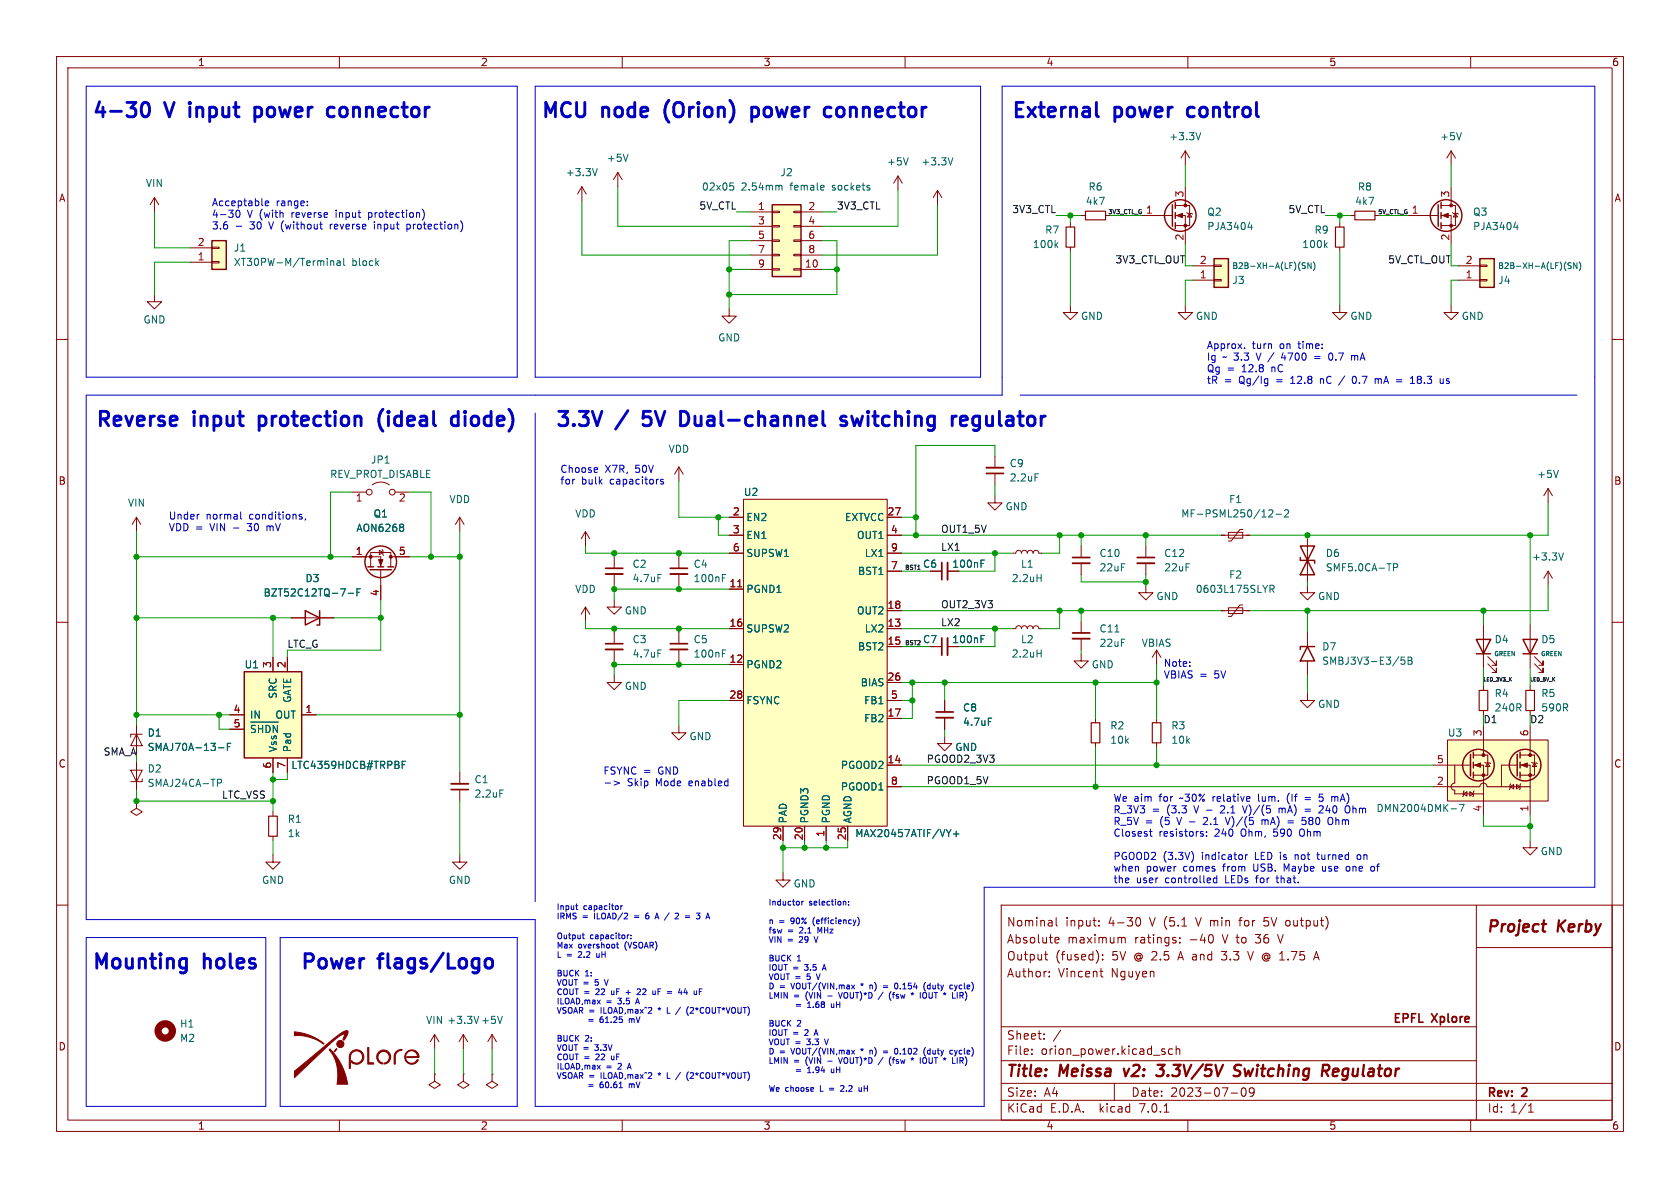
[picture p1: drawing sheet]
<svg xmlns="http://www.w3.org/2000/svg" width="297mm" height="210mm" viewBox="0 0 297 210" stroke-linecap="round" stroke-linejoin="round" font-family="sans-serif">
<defs><g id="words">
<g font-size="3.5" fill="#0000c2">
<text x="16.5" y="21">4-30</text>
<text x="29.6" y="21">V</text>
<text x="34.5" y="21">input</text>
<text x="46.7" y="21">power</text>
<text x="60.4" y="21">connector</text>
<text x="95.9" y="21">MCU</text>
<text x="106.7" y="21">node</text>
<text x="118.5" y="21">(Orion)</text>
<text x="134.6" y="21">power</text>
<text x="148.3" y="21">connector</text>
<text x="179.1" y="21">External</text>
<text x="197.2" y="21">power</text>
<text x="211" y="21">control</text>
<text x="17.1" y="75.6">Reverse</text>
<text x="34.5" y="75.6">input</text>
<text x="46.7" y="75.6">protection</text>
<text x="68.7" y="75.6">(ideal</text>
<text x="82.4" y="75.6">diode)</text>
<text x="98.4" y="75.6">3.3V</text>
<text x="109.3" y="75.6">/</text>
<text x="114.7" y="75.6">5V</text>
<text x="122" y="75.6">Dual-channel</text>
<text x="151.2" y="75.6">switching</text>
<text x="171.5" y="75.6">regulator</text>
<text x="16.5" y="171.5">Mounting</text>
<text x="36.3" y="171.5">holes</text>
<text x="53.3" y="171.5">Power</text>
<text x="67.3" y="171.5">flags/Logo</text>
</g>
<g font-size="2.8" fill="#840000">
<text x="262.7" y="165.3">Project</text>
<text x="275.2" y="165.3">Kerby</text>
<text x="178" y="190.8">Title:</text>
<text x="187.4" y="190.8">Meissa</text>
<text x="199.4" y="190.8">v2:</text>
<text x="205.9" y="190.8">3.3V/5V</text>
<text x="220.1" y="190.8">Switching</text>
<text x="236.2" y="190.8">Regulator</text>
</g>
<g font-size="2.1" fill="#840000">
<text x="178" y="166.9">Absolute</text>
<text x="178" y="163.9">Nominal</text>
<text x="188.4" y="163.9">input:</text>
<text x="188.7" y="166.9">maximum</text>
<text x="195.9" y="163.9">4-30</text>
<text x="200.6" y="166.9">ratings:</text>
<text x="203.3" y="163.9">V (5.1</text>
<text x="210.3" y="166.9">-40</text>
<text x="211.6" y="163.9">V min</text>
<text x="216.3" y="166.9">V to</text>
<text x="219.4" y="163.9">for</text>
<text x="222.2" y="166.9">36</text>
<text x="223.8" y="163.9">5V output)</text>
<text x="226.3" y="166.9">V</text>
<text x="178" y="172.9">Author:</text>
<text x="178" y="169.9">Output</text>
<text x="186.6" y="169.9">(fused):</text>
<text x="187.1" y="172.9">Vincent</text>
<text x="196.4" y="172.9">Nguyen</text>
<text x="196.6" y="169.9">5V @ 2.5</text>
<text x="208.5" y="169.9">A and</text>
<text x="216.3" y="169.9">3.3</text>
<text x="221.1" y="169.9">V @ 1.75</text>
<text x="233" y="169.9">A</text>
<text x="178" y="183.9">Sheet:</text>
<text x="186.2" y="183.9">/</text>
<text x="245.9" y="181.1">EPFL</text>
<text x="252.9" y="181.1">Xplore</text>
<text x="178" y="186.6">File:</text>
<text x="184" y="186.6">orion_power.kicad_sch</text>
<text x="178" y="196.8">KiCad</text>
<text x="178" y="194">Size:</text>
<text x="184.6" y="194">A4</text>
<text x="185.7" y="196.8">E.D.A.</text>
<text x="194.4" y="196.8">kicad</text>
<text x="200" y="194">Date:</text>
<text x="201.5" y="196.8">7.0.1</text>
<text x="206.9" y="194">2023-07-09</text>
<text x="263" y="194.2">Rev:</text>
<text x="263" y="196.8">Id:</text>
<text x="267" y="196.8">1/1</text>
<text x="269.2" y="194.2">2</text>
</g>
<g font-size="1.8" fill="#840000">
<text x="35" y="11.8">1</text>
<text x="85" y="11.8">2</text>
<text x="135" y="11.8">3</text>
<text x="185" y="11.8">4</text>
<text x="235" y="11.8">5</text>
<text x="285" y="11.8">6</text>
<text x="10.4" y="35.8">A</text>
<text x="285.4" y="35.8">A</text>
<text x="10.3" y="85.8">B</text>
<text x="285.3" y="85.8">B</text>
<text x="10.3" y="135.8">C</text>
<text x="285.3" y="135.8">C</text>
<text x="10.3" y="185.8">D</text>
<text x="285.3" y="185.8">D</text>
<text x="35" y="199.8">1</text>
<text x="85" y="199.8">2</text>
<text x="135" y="199.8">3</text>
<text x="185" y="199.8">4</text>
<text x="235" y="199.8">5</text>
<text x="285" y="199.8">6</text>
</g>
<g font-size="1.8" fill="#006464">
<text x="107.2" y="28.8">+5V</text>
<text x="156.8" y="29.4">+5V</text>
<text x="162.8" y="29.4">+3.3V</text>
<text x="206.6" y="25">+3.3V</text>
<text x="254.5" y="25">+5V</text>
<text x="25.7" y="33.2">VIN</text>
<text x="100" y="31.3">+3.3V</text>
<text x="124" y="33.8">02x05</text>
<text x="131" y="33.8">2.54mm</text>
<text x="137.9" y="31.3">J2</text>
<text x="139.7" y="33.8">female</text>
<text x="147.2" y="33.8">sockets</text>
<text x="192.4" y="33.8">R6</text>
<text x="240" y="33.8">R8</text>
<text x="184.7" y="41.5">R7</text>
<text x="191.9" y="36.4">4k7</text>
<text x="213.4" y="38.3">Q2</text>
<text x="213.4" y="40.8">PJA3404</text>
<text x="232.3" y="41.5">R9</text>
<text x="239.5" y="36.4">4k7</text>
<text x="260.4" y="38.3">Q3</text>
<text x="260.4" y="40.8">PJA3404</text>
<text x="41.3" y="44.6">J1</text>
<text x="41.3" y="47.2">XT30PW-M/Terminal</text>
<text x="62.2" y="47.2">block</text>
<text x="182.5" y="44">100k</text>
<text x="230.2" y="44">100k</text>
<text x="217.8" y="50.4">J3</text>
<text x="264.8" y="50.4">J4</text>
<text x="25.3" y="57.3">GND</text>
<text x="191" y="56.7">GND</text>
<text x="211.4" y="56.7">GND</text>
<text x="238.7" y="56.7">GND</text>
<text x="258.4" y="56.7">GND</text>
<text x="126.9" y="60.5">GND</text>
<text x="65.5" y="82.1">JP1</text>
<text x="118.1" y="80.2">VDD</text>
<text x="178.4" y="82.7">C9</text>
<text x="22.6" y="89.7">VIN</text>
<text x="58.3" y="84.6">REV_PROT_DISABLE</text>
<text x="79.4" y="89.1">VDD</text>
<text x="131.5" y="87.8">U2</text>
<text x="178.4" y="85.3">2.2uF</text>
<text x="217.2" y="89.1">F1</text>
<text x="271.7" y="84.6">+5V</text>
<text x="63" y="94.2">AON6268</text>
<text x="66" y="91.6">Q1</text>
<text x="101.6" y="91.6">VDD</text>
<text x="132" y="92.3">EN2</text>
<text x="132" y="95.4">EN1</text>
<text x="149.3" y="92.3">EXTVCC</text>
<text x="151.4" y="95.4">OUT1</text>
<text x="177.7" y="90.4">GND</text>
<text x="208.8" y="91.6">MF-PSML250/12-2</text>
<text x="111.8" y="100.5">C2</text>
<text x="122.6" y="100.5">C4</text>
<text x="132" y="98.6">SUPSW1</text>
<text x="151.6" y="101.8">BST1</text>
<text x="152.8" y="98.6">LX1</text>
<text x="163.1" y="100.5">C6</text>
<text x="168.3" y="100.5">100nF</text>
<text x="180.4" y="100.5">L1</text>
<text x="194.3" y="98.6">C10</text>
<text x="194.3" y="101.2">22uF</text>
<text x="205.7" y="98.6">C12</text>
<text x="205.7" y="101.2">22uF</text>
<text x="234.3" y="98.6">D6</text>
<text x="234.3" y="101.2">SMF5.0CA-TP</text>
<text x="270.8" y="99.3">+3.3V</text>
<text x="46.5" y="105.6">BZT52C12TQ-7-F</text>
<text x="53.9" y="103.1">D3</text>
<text x="101.6" y="105">VDD</text>
<text x="111.8" y="103.1">4.7uF</text>
<text x="122.6" y="103.1">100nF</text>
<text x="132" y="105">PGND1</text>
<text x="178.8" y="103.1">2.2uH</text>
<text x="204.4" y="106.2">GND</text>
<text x="211.3" y="105">0603L175SLYR</text>
<text x="217.2" y="102.4">F2</text>
<text x="233" y="106.2">GND</text>
<text x="110.4" y="108.8">GND</text>
<text x="111.8" y="113.9">C3</text>
<text x="122.6" y="113.9">C5</text>
<text x="132" y="112">SUPSW2</text>
<text x="151.4" y="108.8">OUT2</text>
<text x="152.8" y="112">LX2</text>
<text x="163.1" y="113.9">C7</text>
<text x="168.3" y="113.9">100nF</text>
<text x="180.4" y="113.9">L2</text>
<text x="194.3" y="112">C11</text>
<text x="264.2" y="113.9">D4</text>
<text x="272.4" y="113.9">D5</text>
<text x="43.2" y="118.3">U1</text>
<text x="111.8" y="116.4">4.7uF</text>
<text x="122.6" y="116.4">100nF</text>
<text x="132" y="118.3">PGND2</text>
<text x="151.6" y="115.1">BST2</text>
<text x="178.8" y="116.4">2.2uH</text>
<text x="192.9" y="118.3">GND</text>
<text x="194.3" y="114.5">22uF</text>
<text x="201.8" y="114.5">VBIAS</text>
<text x="233.7" y="115.1">D7</text>
<text x="233.7" y="117.7">SMBJ3V3-E3/5B</text>
<text x="49.1" y="123.6" transform="rotate(-90 49.1 123.6)">SRC</text>
<text x="51.6" y="124.4" transform="rotate(-90 51.6 124.4)">GATE</text>
<text x="110.4" y="122.1">GND</text>
<text x="132" y="124.7">FSYNC</text>
<text x="152" y="121.5">BIAS</text>
<text x="152.6" y="124.7">FB1</text>
<text x="170.2" y="125.9">C8</text>
<text x="233" y="125.3">GND</text>
<text x="264.2" y="123.4">R4</text>
<text x="264.2" y="125.9">240R</text>
<text x="272.4" y="123.4">R5</text>
<text x="272.4" y="125.9">590R</text>
<text x="26" y="130.4">D1</text>
<text x="44.2" y="127.2">IN</text>
<text x="44.2" y="130.3">~{SHDN}</text>
<text x="48.6" y="127.2">OUT</text>
<text x="121.8" y="131">GND</text>
<text x="152.6" y="127.8">FB2</text>
<text x="170.2" y="128.5">4.7uF</text>
<text x="196.2" y="129.1">R2</text>
<text x="196.2" y="131.6">10k</text>
<text x="207" y="129.1">R3</text>
<text x="207" y="131.6">10k</text>
<text x="255.9" y="130.4">U3</text>
<text x="26" y="132.9">SMAJ70A-13-F</text>
<text x="26" y="136.7">D2</text>
<text x="49.1" y="133" transform="rotate(-90 49.1 133)">Vss</text>
<text x="51.4" y="136.1">LTC4359HDCB#TRPBF</text>
<text x="51.6" y="133" transform="rotate(-90 51.6 133)">Pad</text>
<text x="148.5" y="136.1">PGOOD2</text>
<text x="168.8" y="132.9">GND</text>
<text x="26" y="139.3">SMAJ24CA-TP</text>
<text x="83.8" y="138.6">C1</text>
<text x="83.8" y="141.2">2.2uF</text>
<text x="148.5" y="139.9">PGOOD1</text>
<text x="50.8" y="145.6">R1</text>
<text x="50.8" y="148.1">1k</text>
<text x="139.3" y="145.5" transform="rotate(-90 139.3 145.5)">PAD</text>
<text x="143.1" y="145.5" transform="rotate(-90 143.1 145.5)">PGND3</text>
<text x="146.9" y="145.5" transform="rotate(-90 146.9 145.5)">PGND</text>
<text x="150.7" y="145.5" transform="rotate(-90 150.7 145.5)">AGND</text>
<text x="151.1" y="148.1">MAX20457ATIF/VY+</text>
<text x="272.3" y="151.3">GND</text>
<text x="46.3" y="156.4">GND</text>
<text x="79.3" y="156.4">GND</text>
<text x="140.2" y="157">GND</text>
<text x="31.8" y="181.8">H1</text>
<text x="31.8" y="184.3">M2</text>
<text x="75.3" y="181.2">VIN +3.3V</text>
<text x="85" y="181.2">+5V</text>
</g>
<g font-size="1.8" fill="#a90000">
<text x="209.3" y="35" transform="rotate(-90 209.3 35)">3</text>
<text x="256.3" y="35" transform="rotate(-90 256.3 35)">3</text>
<text x="134" y="37.2">1</text>
<text x="134" y="39.8">3</text>
<text x="142.8" y="37.2">2</text>
<text x="142.8" y="39.8">4</text>
<text x="202.5" y="37.8">1</text>
<text x="249.5" y="37.8">1</text>
<text x="34.9" y="46.1">1</text>
<text x="34.9" y="43.6">2</text>
<text x="134" y="42.3">5</text>
<text x="134" y="44.8">7</text>
<text x="134" y="47.4">9</text>
<text x="142.2" y="47.4">10</text>
<text x="142.8" y="42.3">6</text>
<text x="142.8" y="44.8">8</text>
<text x="209.3" y="42.6" transform="rotate(-90 209.3 42.6)">2</text>
<text x="212.1" y="46.7">2</text>
<text x="256.3" y="42.6" transform="rotate(-90 256.3 42.6)">2</text>
<text x="259" y="46.7">2</text>
<text x="212.1" y="49.3">1</text>
<text x="259" y="49.3">1</text>
<text x="62.8" y="88.9">1</text>
<text x="70.5" y="88.9">2</text>
<text x="129.5" y="91.2">2</text>
<text x="129.5" y="94.4">3</text>
<text x="156.8" y="91.2">27</text>
<text x="157.4" y="94.4">4</text>
<text x="62.8" y="98.2">1</text>
<text x="70.5" y="98.2">5</text>
<text x="129.5" y="97.5">6</text>
<text x="157.4" y="100.7">7</text>
<text x="157.4" y="97.5">9</text>
<text x="67.1" y="105.4" transform="rotate(-90 67.1 105.4)">4</text>
<text x="128.9" y="103.9">11</text>
<text x="156.8" y="107.7">18</text>
<text x="128.9" y="110.9">16</text>
<text x="156.8" y="110.9">13</text>
<text x="48" y="118.1" transform="rotate(-90 48 118.1)">3</text>
<text x="50.5" y="118.1" transform="rotate(-90 50.5 118.1)">2</text>
<text x="128.9" y="117.2">12</text>
<text x="156.8" y="114">15</text>
<text x="128.9" y="123.6">28</text>
<text x="156.8" y="120.4">26</text>
<text x="157.4" y="123.6">5</text>
<text x="41.2" y="126.1">4</text>
<text x="41.2" y="128.7">5</text>
<text x="53.9" y="126.1">1</text>
<text x="156.8" y="126.7">17</text>
<text x="262" y="130.2" transform="rotate(-90 262 130.2)">3</text>
<text x="270.3" y="130.2" transform="rotate(-90 270.3 130.2)">6</text>
<text x="48" y="135.9" transform="rotate(-90 48 135.9)">6</text>
<text x="50.5" y="135.9" transform="rotate(-90 50.5 135.9)">7</text>
<text x="156.8" y="135">14</text>
<text x="254" y="135">5</text>
<text x="157.4" y="138.8">8</text>
<text x="254" y="138.8">2</text>
<text x="262" y="143.5" transform="rotate(-90 262 143.5)">4</text>
<text x="270.3" y="143.5" transform="rotate(-90 270.3 143.5)">1</text>
<text x="138.2" y="148.6" transform="rotate(-90 138.2 148.6)">29</text>
<text x="142" y="148.6" transform="rotate(-90 142 148.6)">20</text>
<text x="145.8" y="148" transform="rotate(-90 145.8 148)">1</text>
<text x="149.6" y="148.6" transform="rotate(-90 149.6 148.6)">25</text>
</g>
<g font-size="1.8" fill="#0000c2">
<text x="37.5" y="36.5">Acceptable</text>
<text x="37.5" y="38.6">4-30</text>
<text x="37.5" y="40.6">3.6</text>
<text x="43.8" y="38.6">V (with</text>
<text x="44.3" y="40.6">30</text>
<text x="47.8" y="40.6">V (without</text>
<text x="48.8" y="36.5">range:</text>
<text x="51.7" y="38.6">reverse</text>
<text x="58.7" y="40.6">reverse</text>
<text x="59.6" y="38.6">input</text>
<text x="65.5" y="38.6">protection)</text>
<text x="66.7" y="40.6">input</text>
<text x="72.5" y="40.6">protection)</text>
<text x="213.4" y="61.8">Approx.</text>
<text x="213.4" y="63.8">Ig</text>
<text x="213.4" y="65.9">Qg =</text>
<text x="216.2" y="63.8">~ 3.3</text>
<text x="219.6" y="65.9">12.8</text>
<text x="221.4" y="61.8">turn</text>
<text x="222.3" y="63.8">V /</text>
<text x="224.9" y="65.9">nC</text>
<text x="226.3" y="61.8">on</text>
<text x="226.9" y="63.8">4700</text>
<text x="229.7" y="61.8">time:</text>
<text x="232.9" y="63.8">=</text>
<text x="235.5" y="63.8">0.7</text>
<text x="239.7" y="63.8">mA</text>
<text x="213.4" y="67.9">tR</text>
<text x="216.5" y="67.9">=</text>
<text x="219.1" y="67.9">Qg/Ig</text>
<text x="225.8" y="67.9">=</text>
<text x="228.4" y="67.9">12.8</text>
<text x="233.8" y="67.9">nC</text>
<text x="237.3" y="67.9">/</text>
<text x="239.7" y="67.9">0.7</text>
<text x="243.8" y="67.9">mA =</text>
<text x="250.4" y="67.9">18.3</text>
<text x="255.7" y="67.9">us</text>
<text x="99.1" y="83.7">Choose</text>
<text x="107" y="83.7">X7R,</text>
<text x="112.4" y="83.7">50V</text>
<text x="99.1" y="85.7">for</text>
<text x="102.8" y="85.7">bulk</text>
<text x="107.9" y="85.7">capacitors</text>
<text x="29.8" y="91.9">Under</text>
<text x="29.8" y="94">VDD =</text>
<text x="36.4" y="91.9">normal</text>
<text x="37.2" y="94">VIN -</text>
<text x="44" y="94">30</text>
<text x="44.1" y="91.9">conditions,</text>
<text x="47.5" y="94">mV</text>
<text x="205.7" y="118">Note:</text>
<text x="205.7" y="120">VBIAS =</text>
<text x="214.8" y="120">5V</text>
<text x="106.7" y="137">FSYNC =</text>
<text x="116.4" y="137">GND</text>
<text x="110.9" y="139.1">Skip</text>
<text x="116" y="139.1">Mode</text>
<text x="121.9" y="139.1">enabled</text>
<text x="196.8" y="141.8">We aim</text>
<text x="196.8" y="143.9">R_3V3</text>
<text x="203.7" y="143.9">=</text>
<text x="205" y="141.8">for</text>
<text x="206.4" y="143.9">(3.3</text>
<text x="208.8" y="141.8">~30%</text>
<text x="211.3" y="143.9">V -</text>
<text x="214.7" y="141.8">relative</text>
<text x="216.2" y="143.9">2.1</text>
<text x="220.3" y="143.9">V)/(5</text>
<text x="222.8" y="141.8">lum.</text>
<text x="226.7" y="143.9">mA)</text>
<text x="228" y="141.8">(If</text>
<text x="234" y="141.8">5</text>
<text x="234.1" y="143.9">240</text>
<text x="236.3" y="141.8">mA)</text>
<text x="238.8" y="143.9">Ohm DMN2004DMK-7</text>
<text x="196.8" y="145.9">R_5V =</text>
<text x="196.8" y="148">Closest</text>
<text x="204.9" y="148">resistors:</text>
<text x="205.1" y="145.9">(5</text>
<text x="208.3" y="145.9">V -</text>
<text x="213.1" y="145.9">2.1</text>
<text x="214.8" y="148">240</text>
<text x="217.3" y="145.9">V)/(5</text>
<text x="219.5" y="148">Ohm,</text>
<text x="223.7" y="145.9">mA)</text>
<text x="225.4" y="148">590</text>
<text x="230.1" y="148">Ohm</text>
<text x="231.1" y="145.9">580</text>
<text x="235.8" y="145.9">Ohm</text>
<text x="196.8" y="152.1">PGOOD2 (3.3V)</text>
<text x="196.8" y="154.2">when</text>
<text x="202.7" y="154.2">power</text>
<text x="209.3" y="154.2">comes</text>
<text x="212.5" y="152.1">indicator</text>
<text x="216.4" y="154.2">from</text>
<text x="221.9" y="154.2">USB.</text>
<text x="222" y="152.1">LED is</text>
<text x="227.4" y="154.2">Maybe</text>
<text x="229.3" y="152.1">not</text>
<text x="233.4" y="152.1">turned</text>
<text x="234.3" y="154.2">use</text>
<text x="238.6" y="154.2">one</text>
<text x="240.6" y="152.1">on</text>
<text x="243.1" y="154.2">of</text>
<text x="196.8" y="156.2">the</text>
<text x="200.9" y="156.2">user</text>
<text x="206.1" y="156.2">controlled</text>
<text x="216.8" y="156.2">LEDs</text>
<text x="222.3" y="156.2">for</text>
<text x="226.1" y="156.2">that.</text>
</g>
<g font-size="1.8" fill="#0f0f0f">
<text x="123.5" y="37.1">5V_CTL</text>
<text x="148" y="37.1">3V3_CTL</text>
<text x="178.8" y="37.8">3V3_CTL</text>
<text x="227.7" y="37.8">5V_CTL</text>
<text x="197.1" y="46.6">3V3_CTL_OUT</text>
<text x="245.3" y="46.6">5V_CTL_OUT</text>
<text x="166.4" y="94.3">OUT1_5V</text>
<text x="166.4" y="97.4">LX1</text>
<text x="166.4" y="107.6">OUT2_3V3</text>
<text x="166.4" y="110.8">LX2</text>
<text x="50.8" y="114.6">LTC_G</text>
<text x="18.2" y="133.6">SMA_A</text>
<text x="163.8" y="134.9">PGOOD2_3V3</text>
<text x="39.1" y="141.3">LTC_VSS</text>
<text x="163.8" y="138.7">PGOOD1_5V</text>
</g>
<g font-size="1.8" fill="#009600">
<text x="262.3" y="127.9">D1</text>
<text x="270.5" y="127.9">D2</text>
</g>
<g font-size="1.4" fill="#006464">
<text x="217.8" y="47.7">B2B-XH-A(LF)(SN)</text>
<text x="264.8" y="47.7">B2B-XH-A(LF)(SN)</text>
</g>
<g font-size="1.4" fill="#0000c2">
<text x="98.4" y="160.9">Input</text>
<text x="103.2" y="160.9">capacitor</text>
<text x="135.9" y="160.1">Inductor</text>
<text x="143.1" y="160.1">selection:</text>
<text x="98.4" y="166.1">Output</text>
<text x="98.4" y="167.7">Max</text>
<text x="98.4" y="162.6">IRMS</text>
<text x="102.3" y="167.7">overshoot</text>
<text x="103" y="162.6">=</text>
<text x="104.4" y="166.1">capacitor:</text>
<text x="105.2" y="162.6">ILOAD/2</text>
<text x="110.6" y="167.7">(VSOAR)</text>
<text x="112.5" y="162.6">=</text>
<text x="114.7" y="162.6">6</text>
<text x="116.6" y="162.6">A /</text>
<text x="122.3" y="162.6">=</text>
<text x="124.6" y="162.6">3</text>
<text x="135.9" y="163.4">n</text>
<text x="135.9" y="165.1">fsw</text>
<text x="135.9" y="166.7">VIN</text>
<text x="137.8" y="163.4">=</text>
<text x="139.3" y="166.7">=</text>
<text x="139.3" y="165.1">=</text>
<text x="140" y="163.4">90%</text>
<text x="141.5" y="166.7">29</text>
<text x="141.5" y="165.1">2.1</text>
<text x="144" y="163.4">(efficiency)</text>
<text x="144.4" y="166.7">V</text>
<text x="144.9" y="165.1">MHz</text>
<text x="98.4" y="169.4">L =</text>
<text x="98.4" y="172.7">BUCK</text>
<text x="102.4" y="169.4">2.2</text>
<text x="103.5" y="172.7">1:</text>
<text x="105.8" y="169.4">uH</text>
<text x="135.9" y="170">BUCK</text>
<text x="135.9" y="171.6">IOUT =</text>
<text x="135.9" y="173.3">VOUT =</text>
<text x="141" y="170">1</text>
<text x="142.4" y="171.6">3.5</text>
<text x="142.8" y="173.3">5</text>
<text x="144.7" y="173.3">V</text>
<text x="145.8" y="171.6">A</text>
<text x="98.4" y="174.3">VOUT =</text>
<text x="98.4" y="175.9">COUT =</text>
<text x="98.4" y="177.6">ILOAD,max</text>
<text x="98.4" y="179.2">VSOAR =</text>
<text x="105.4" y="174.3">5</text>
<text x="105.5" y="175.9">22</text>
<text x="106.4" y="179.2">ILOAD,max^2</text>
<text x="107.2" y="177.6">=</text>
<text x="107.3" y="174.3">V</text>
<text x="108.4" y="175.9">uF</text>
<text x="109.4" y="177.6">3.5</text>
<text x="111.1" y="175.9">+</text>
<text x="112.8" y="177.6">A</text>
<text x="113.3" y="175.9">22</text>
<text x="116.2" y="175.9">uF</text>
<text x="116.7" y="179.2">*</text>
<text x="121.2" y="175.9">44</text>
<text x="122.2" y="179.2">(2*COUT*VOUT)</text>
<text x="135.9" y="174.9">D =</text>
<text x="135.9" y="176.6">LMIN</text>
<text x="140.1" y="174.9">VOUT/(VIN,max</text>
<text x="140.4" y="176.6">=</text>
<text x="141.6" y="178.2">=</text>
<text x="142.6" y="176.6">(VIN</text>
<text x="143.8" y="178.2">1.68</text>
<text x="146.6" y="176.6">-</text>
<text x="148.1" y="178.2">uH</text>
<text x="148.8" y="176.6">VOUT)*D</text>
<text x="152.5" y="174.9">*</text>
<text x="154.3" y="174.9">n)</text>
<text x="158.1" y="176.6">(fsw</text>
<text x="159" y="174.9">0.154</text>
<text x="162.1" y="176.6">*</text>
<text x="163.9" y="176.6">IOUT *</text>
<text x="164.3" y="174.9">(duty</text>
<text x="169.1" y="174.9">cycle)</text>
<text x="169.9" y="176.6">LIR)</text>
<text x="98.4" y="184.2">BUCK</text>
<text x="98.4" y="185.8">VOUT =</text>
<text x="103.5" y="184.2">2:</text>
<text x="105.1" y="180.9">=</text>
<text x="105.4" y="185.8">3.3V</text>
<text x="107.3" y="180.9">61.25</text>
<text x="112.6" y="180.9">mV</text>
<text x="135.9" y="181.5">BUCK</text>
<text x="135.9" y="183.2">IOUT =</text>
<text x="135.9" y="184.8">VOUT =</text>
<text x="141" y="181.5">2</text>
<text x="142.4" y="183.2">2</text>
<text x="142.8" y="184.8">3.3</text>
<text x="144.4" y="183.2">A</text>
<text x="146.2" y="184.8">V</text>
<text x="98.4" y="187.5">COUT =</text>
<text x="98.4" y="189.1">ILOAD,max</text>
<text x="98.4" y="190.8">VSOAR =</text>
<text x="105.5" y="187.5">22</text>
<text x="106.4" y="190.8">ILOAD,max^2</text>
<text x="107.2" y="189.1">=</text>
<text x="108.4" y="187.5">uF</text>
<text x="109.4" y="189.1">2</text>
<text x="111.3" y="189.1">A</text>
<text x="116.7" y="190.8">*</text>
<text x="122.2" y="190.8">(2*COUT*VOUT)</text>
<text x="135.9" y="186.5">D =</text>
<text x="135.9" y="188.1">LMIN</text>
<text x="140.1" y="186.5">VOUT/(VIN,max</text>
<text x="140.4" y="188.1">=</text>
<text x="141.6" y="189.7">=</text>
<text x="142.6" y="188.1">(VIN</text>
<text x="143.8" y="189.7">1.94</text>
<text x="146.6" y="188.1">-</text>
<text x="148.1" y="189.7">uH</text>
<text x="148.8" y="188.1">VOUT)*D</text>
<text x="152.5" y="186.5">*</text>
<text x="154.3" y="186.5">n)</text>
<text x="158.1" y="188.1">(fsw</text>
<text x="159" y="186.5">0.102</text>
<text x="162.1" y="188.1">*</text>
<text x="163.9" y="188.1">IOUT *</text>
<text x="164.3" y="186.5">(duty</text>
<text x="169.1" y="186.5">cycle)</text>
<text x="169.9" y="188.1">LIR)</text>
<text x="105.1" y="192.4">=</text>
<text x="107.3" y="192.4">60.61</text>
<text x="112.6" y="192.4">mV</text>
<text x="135.9" y="193">We choose</text>
<text x="145.1" y="193">L =</text>
<text x="149.1" y="193">2.2</text>
<text x="152.5" y="193">uH</text>
</g>
<g font-size="1.1" fill="#0f0f0f">
<text x="195.7" y="37.9">3V3_CTL_G</text>
<text x="243.4" y="37.9">5V_CTL_G</text>
<text x="160" y="100.8">BST1</text>
<text x="160" y="114.1">BST2</text>
</g>
<g font-size="1.1" fill="#006464">
<text x="264.1" y="116.1">GREEN</text>
<text x="272.3" y="116.1">GREEN</text>
</g>
<g font-size=".9" fill="#0f0f0f">
<text x="262.3" y="120.5">LED_3V3_K</text>
<text x="270.5" y="120.5">LED_5V_K</text>
</g>
</g></defs>
<g fill="none" stroke="#840000" stroke-width=".18">
<path d="M10 10h277v190h-277zM12 12h273v186h-273zM60 10v2M110 10v2M160 10v2M210 10v2M260 10v2M27.3 34.9v2.6M27.3 34.9l-.8 1.3M27.3 34.9l.8 1.3M102.9 33l-.8 1.3M102.9 33v2.6"/>
<path d="M102.9 33l.7 1.3M109.2 30.5l-.7 1.3M109.2 30.5v2.5M109.2 30.5l.8 1.3M132.7 37.5h3.8M136.5 39.9h1.3v.2h-1.3zM136.5 37.3h1.3v.3h-1.3zM140.3 39.9h1.3v.2h-1.3zM140.3 37.3h1.3v.3h-1.3zM141.6 37.5h3.8M158.7 31.1l-.7 1.3M158.7 31.1v2.6"/>
<path d="M158.7 31.1l.8 1.3M165.7 33.7l-.7 1.2M165.7 33.7v2.5M165.7 33.7l.8 1.2M189.2 39.4v.7M191.1 38.1h.8M201.9 38.1h5.4M207.8 38.1h1.7v5.1M207.8 36.3h2.5v3.6h-2.5M209.5 26.7l-.7 1.2M209.5 26.7v2.5M209.5 33v3.3"/>
<path d="M209.5 26.7l.8 1.2M209.8 37.6l.1 .1h.8l.1 .1M210.3 37.7l.4 .7h-.8zM236.9 39.4v.7M238.8 38.1h.7M243.1 38.1h.7M248.9 38.1h5.4M254.8 38.1h1.7v5.1M254.8 36.3h2.5v3.6h-2.5M256.5 26.7l-.7 1.2M256.5 26.7v2.5M256.5 33v3.3"/>
<path d="M256.5 26.7l.8 1.2M256.8 37.6l.1 .1h.8l.1 .1M257.3 37.7l.4 .7h-.8zM10 60h2M27.3 52.1v1.2h1.3l-1.3 1.3-1.3-1.3h1.3M33.7 46.4h3.8M33.7 43.8h3.8M37.5 43.7h1.2v.2h-1.2zM37.5 46.2h1.2v.3h-1.2zM128.9 54.6v1.3h1.3l-1.3 1.3-1.3-1.3h1.3M132.7 47.6h3.8M132.7 40h3.8"/>
<path d="M132.7 42.5h3.8M132.7 45.1h3.8M136.5 47.5h1.3v.3h-1.3zM136.5 45h1.3v.2h-1.3zM136.5 42.4h1.3v.3h-1.3zM140.3 47.5h1.3v.3h-1.3zM140.3 45h1.3v.2h-1.3zM140.3 42.4h1.3v.3h-1.3zM141.6 47.6h3.8M141.6 40h3.8M141.6 42.5h3.8M141.6 45.1h3.8"/>
<path d="M189.2 54v1.2h1.3l-1.3 1.3-1.2-1.3h1.2M189.2 43.7v.8M209.5 54v1.2h1.3l-1.3 1.3-1.2-1.3h1.2M210.8 49.5h3.8M210.8 47h3.8M214.6 46.9h1.3v.2h-1.3zM214.6 49.4h1.3v.3h-1.3zM236.9 54v1.2h1.2l-1.2 1.3-1.3-1.3h1.3M236.9 43.7v.8M256.5 54v1.2h1.3l-1.3 1.3-1.2-1.3h1.2M257.8 49.5h3.8M257.8 47h3.8"/>
<path d="M261.6 46.9h1.3v.2h-1.3zM261.6 49.4h1.3v.3h-1.3zM285 60h2M24.1 91.4v2.6M24.1 91.4l-.7 1.3M24.1 91.4l.8 1.3M62.2 98.4h5.1v1.8M62.2 87h2.6M65.8 85.7a2.54 2.54 0 0 1 3 0M67.1 97.3l.6 .4-.6 .3zM67.6 97.2l.1 .1v.7l.1 .2M69.1 98.4h3.3"/>
<path d="M69.8 87h2.6M81.3 91.4l-.8 1.3M81.3 91.4v2.6M81.3 91.4l.7 1.3M103.5 94l-.8 1.3M103.5 94v2.5M103.5 94l.8 1.3M108.6 98.4v2.1M120 82.6v2.5M120 98.4v2.1M120 82.6l-.7 1.2M120 82.6l.8 1.2"/>
<path d="M128.9 94.6h2.5M128.9 91.4h2.5M128.9 97.8h2.5M131.4 88.3h25.4v57.8h-25.4zM156.8 94.6h2.6M156.8 91.4h2.6M156.8 97.8h2.6M175.9 87.6v1.3h1.3l-1.3 1.3-1.3-1.3h1.3M175.9 80.6v2.1M175.9 83.7v2M179.1 97.8h.5l.1-.4 .4-.1 .4 .1 .1 .4 .1-.4 .4-.1 .4 .1 .1 .4 .2-.4 .3-.1 .4 .1 .1 .4 .2-.4 .3-.1 .4 .1 .1 .4h.5M191.1 96.5v2.1"/>
<path d="M191.1 99.6v2M202.6 96.5v2.1M202.6 99.6v2M215.9 94.6h5.1M217.2 94.1h2.5v1h-2.5zM219.7 93.6h-.5l-1.5 2h-.5M231.1 95.3v7.6M273.7 86.4l-.8 1.2M273.7 86.4v2.5M273.7 86.4l.7 1.2M10 110h2M48.3 116.2v2.5"/>
<path d="M50.8 116.2v2.5M51.4 109.2h7.7M65.5 100.2v-2.5h3.6v2.5M67.3 100.7v5.3M103.5 107.3v2.6M103.5 107.3l-.8 1.3M103.5 107.3l.8 1.3M108.6 106v1.3h1.3l-1.3 1.3-1.3-1.3h1.3M108.6 119.4v1.3h1.3l-1.3 1.2-1.3-1.2h1.3M108.6 101.5v2M108.6 111.8v2M108.6 114.8v2"/>
<path d="M120 101.5v2M120 111.8v2M120 114.8v2M128.9 111.1h2.5M128.9 104.1h2.5M128.9 117.5h2.5M156.8 101h2.6M156.8 108h2.6M156.8 111.1h2.6M156.8 114.3h2.6M164.5 101h2M164.5 114.3h2"/>
<path d="M167.5 101h2M167.5 114.3h2M179.1 111.1h.5l.1-.3 .4-.2 .4 .2 .1 .3 .1-.3 .4-.2 .4 .2 .1 .3 .2-.3 .3-.2 .4 .2 .1 .3 .2-.3 .3-.2 .4 .2 .1 .3h.5M191.1 115.6v1.2h1.3l-1.3 1.3-1.2-1.3h1.2M191.1 109.9v2M191.1 112.9v2M202.6 103.5v1.3h1.2l-1.2 1.2-1.3-1.2h1.3M204.5 114.9v2.6M204.5 114.9l-.8 1.3M204.5 114.9l.7 1.3M215.9 108h5.1M217.2 107.4h2.5v1.1h-2.5z"/>
<path d="M219.7 106.9h-.5l-1.5 2.1h-.5M231.1 103.5v1.3h1.3l-1.3 1.2-1.2-1.2h1.2M231.1 111.8v2.5M231.1 116.8v2.6M262.3 110.5v7.6M263 117.3l1.5 1.6v-.8v.8h-.7M263 116.1l1.5 1.5v-.8v.8h-.7M270.5 110.5v7.6M271.3 117.3l1.5 1.6v-.8v.8h-.8M271.3 116.1l1.5 1.5v-.8v.8h-.8M273.7 101v2.5M273.7 101l-.8 1.2"/>
<path d="M273.7 101l.7 1.2M285 110h2M23.1 136.1h2l-1 2.1zM24.1 129.8l1 2h-2zM24.1 128.3v5.1M24.1 134.6v5.1M25.1 129.8h-2v.5M25.1 137.7v.5h-2M40.6 126.4h2.6M40.6 128.9h2.6M48.3 134v2.5M50.8 134v2.5"/>
<path d="M53.3 126.4h2.6M81.3 136.5v2.1M81.3 139.6v2M120 128.3v1.2h1.3l-1.3 1.3-1.3-1.3h1.3M128.9 123.8h2.5M156.8 135.3h2.6M156.8 139.1h2.6M156.8 127h2.6M156.8 120.7h2.6M156.8 123.8h2.6M167 130.2v1.2h1.3l-1.3 1.3-1.3-1.3h1.3M167 123.8v2.1"/>
<path d="M167 126.9v2M193.7 127v.8M193.7 131.3v.8M204.5 127v.8M204.5 131.3v.8M231.1 122.6v1.2h1.3l-1.3 1.3-1.2-1.3h1.2M253.4 135.3h6.6M255.9 130.8h17.8v10.8h-17.8zM257.2 135.3v3.1a.63 .63 0 0 0-.7 .7 .63 .63 0 0 0 .7 .6v.6h5.1M258.8 139.8l-.1 .2v.7l-.1 .1M259.8 140l.7 .3-.7 .4zM260.5 135.3h1.8v8.8"/>
<path d="M260.5 133.5h2.5v3.5h-2.5M260.6 139.8l-.1 .2v.7l-.2 .1M262.3 121.3v.7M262.3 125.6v.8M262.3 128.3v5.2M262.5 134.7l.1 .2h.8l.1 .1M263 134.9l.4 .6h-.8zM265.4 139.1h5.1M267 139.1l.6-.4v.7zM267.1 138.6l-.1 .1v.7l-.2 .2M268.1 138.7l.6 .4-.6 .3zM268.2 135.3h-2.8v3.8h-2.5a.63 .63 0 0 0-.6-.7 .63 .63 0 0 0-.7 .7h-8.2"/>
<path d="M268.7 135.3h1.8v8.8M268.7 133.5h2.6v3.5h-2.6M268.9 138.6l-.2 .1v.7l-.1 .2M270.5 121.3v.7M270.5 125.6v.8M270.5 128.3v5.2M270.8 134.7l.1 .2h.8l.1 .1M271.3 134.9l.4 .6h-.8zM10 160h2M24.1 141.6v1.3l1 .6-1 .6-1-.6 1-.6M24.1 141.6h.1M48.3 151.1v1.3h1.2l-1.2 1.3-1.3-1.3h1.3"/>
<path d="M48.3 143.5v.8M48.3 147.8v.8M81.3 151.1v1.3h1.2l-1.2 1.3-1.3-1.3h1.3M138.4 154.3v1.3h1.3l-1.3 1.2-1.2-1.2h1.2M138.4 146.1v2.5M142.2 146.1v2.5M146 146.1v2.5M149.9 146.1v2.5M258.7 140.3l.6-.3v.7zM270.5 148.6v1.3h1.3l-1.3 1.2-1.3-1.2h1.3M285 160h2M177 160h108v38h-108z"/>
<path d="M184.6 168.7h.6M184.9 169.6l.3 .1M185.5 172.6v.1M185.5 171.8v.1M186.7 165.7l.4 .1 .1 .3-.7 .1M186.7 162.2v1.3l.2 .2M187.1 166.6l-.4 .1M194.1 168.6v1M194.3 163.6v.1M194.3 162.8v.1M194.4 171.7h.6M194.7 172.6l.3 .1"/>
<path d="M194.9 169.6v.1M194.9 168.8v.1M198.4 165.8h.5v.9M200.9 162.3l.2-.1a.81 .81 0 0 1 .6 .6 .81 .81 0 0 1-.3 .8l-.1 .1a.81 .81 0 0 1-.4-1.4zM208.6 165.8v.1M208.6 166.6v.1M208.9 163.7h.9M213.9 165.3l.1-.1a.81 .81 0 0 1 .6 .6 .81 .81 0 0 1-.3 .8h-.4M232.7 168.2l-.5 1.5M261 160v38M261 167.5h24M60 198v2"/>
<path d="M76.8 189.9v1.2l1.1 .7-1.1 .6-1-.6 1-.7M76.8 189.9h.1M76.8 182.9v2.5M76.8 182.9l-.7 1.3M76.8 182.9l.8 1.3M81.9 189.9v1.2l1 .7-1 .6-1-.6 1-.7M81.9 189.9h.1M81.9 182.9l-.7 1.3M81.9 182.9v2.5M81.9 182.9l.8 1.3M87 189.9v1.2l1 .7-1 .6-1-.6 1-.7M87 189.9h.1"/>
<path d="M87 182.9l-.8 1.3M87 182.9v2.5M87 182.9l.8 1.3M110 198v2M160 198v2M177 194.5h108M177 191.5h108M177 187.5h84M177 181.5h84M182.4 186.3v.1M182.4 185.5v.1M184.6 183.6v.1"/>
<path d="M184.6 182.8v.1M197 191.5v3M205.8 196.6h.8M205.9 186v.3M207.3 185.5l-.4-.1-.3 .3v.4l.1 .2h.6M207.9 185.5l.2-.1 .4 .1 .1 .9M207.9 184.9v1.5M210 198v2M217.6 193.2h1.2M219.6 192.4a1 1 0 0 0 .2 1.4 .81 .81 0 0 0 .6-.6 .81 .81 0 0 0-.3-.8M221 192.4l-.1 .2 .1 .6h.4l.3-.3M221.6 192.4a.99 .99 0 0 1-.3 1.4h-.3"/>
<path d="M260 198v2M270.2 196.6h.9M270.2 195.5l.4-.4v1.5"/>
<circle cx="65.3" cy="87" r=".51"/>
<circle cx="69.3" cy="87" r=".51"/>
</g>
<path d="M272.6 163.3h.7M198.7 188.9l.3 1.3M204.5 190.1l.7 .1M204.6 188.2h1.3l-.8 .8h.3M219.4 188.3a.85 .85 0 0 0-1 .1 .45 .45 0 0 0 .2 .8l.3 .1a.49 .49 0 0 1 .4 .5 .49 .49 0 0 1-.5 .4l-.7-.1M233.9 188.2l1 .1a.58 .58 0 0 1-.3 1h-.8M234.3 189.3l.5 .9" fill="none" stroke="#840000" stroke-width=".4"/>
<path d="M167.5 99.4v3.1M174.4 82.7h3M189.6 99.6h3.1M201 99.6h3.1M107.1 101.5h3M107.1 114.8h3M118.5 101.5h3M118.5 114.8h3M167.5 112.8v3M189.6 112.9h3.1M79.8 138.6h3M165.5 126.9h3" fill="none" stroke="#840000" stroke-width=".33"/>
<path d="M166.5 99.4v3.1M174.4 83.7h3M189.6 98.6h3.1M201 98.6h3.1M107.1 100.5h3M107.1 113.8h3M118.5 100.5h3M118.5 113.8h3M166.5 112.8v3M189.6 111.9h3.1M79.8 139.6h3M165.5 125.9h3" fill="none" stroke="#840000" stroke-width=".3"/>
<g fill="none" stroke="#006464" stroke-width=".18">
<path d="M105.6 29.8l-.4 1.3M111 27.3l-.4 1.2M129.1 32.3h.6M129.2 32.8h.3l.2 .3v.4l-.5 .1M137.9 32.8l.3 .1v.7M145.5 32.8l.2 .3-.6 .1M145.6 33.5l-.1 .1M153.7 33.2v.3M160.6 27.9l-.5 1.3M168.5 27.9l-.5 1.3M212.3 23.4l-.5 1.3M221.2 39.7v.9"/>
<path d="M258.4 23.4l-.5 1.3M268.2 39.7v.9M58.5 46.1v.8M58.5 46.2l.1-.1 .3 .1 .1 .7M59.6 46.2h.5l.1 .7M60.2 46.4l-.5 .1-.2 .1 .2 .3h.5M60.8 45.7v1.1l.1 .1M66.6 46.5l.3 .4M66.9 46.1l-.5 .5M186.6 43.3l.4 .5M187 42.9l-.5 .5M220.6 40.2h.8"/>
<path d="M230.2 46.7l.6 .5-.2 .3-.4-.1M230.8 46.5l-.4-.1-.2 .2M231.8 46.4v1.1l-.6-1.1v1.1M232.2 46.3a1.17 1.17 0 0 1 0 1.5M234.3 43.3l.3 .5M234.6 42.9l-.4 .5M267.6 40.2h.8M277.8 46.5l-.4-.1-.2 .2 .1 .3 .4 .2v.3h-.5M278.8 46.4v1.1l-.6-1.1v1.1M279.2 46.3a1.17 1.17 0 0 1 0 1.5M71.2 92.7l.2 .2-.2 .2M71.2 93.3l.2 .1-.2 .5"/>
<path d="M173.4 99h.6M183 83.8h.6M224.3 90.2l.5-.1 .2 .4-.8 .9h.8M225.6 90.9h.9M227.1 90.2l.5-.1 .2 .4-.8 .9h.8M246.4 99.6h.4l.3 .3-.1 .4h-.6M275.5 83.1l-.4 1.3M276.4 97.7l-.4 1.3M61.5 104.9h1M63.1 104.7h.4M63.7 104.1h-.6v1.3M116.3 101.6h.6"/>
<path d="M116.3 114.9h.6M127.7 101.6h.6M127.7 114.9h.6M173.4 112.3h.6M183.3 115.5h.8M183.3 102.2h.8M184.1 101.6v1.2M184.1 114.9v1.3M224.5 104.1h.6l.1-.2v-.3l-.7-.1v1.2M224.8 104.1l.4 .6M248.3 116.2h-.6v.6l.1-.2 .5 .1 .1 .2-.1 .4-.2 .1-.4-.1M248.9 116.2h.5l.2 .2-.2 .4 .2 .1 .1 .3-.3 .2h-.5z"/>
<path d="M248.9 116.8h.5M38.4 137.7h.5l.3 .3-.2 .4h-.6M38.6 132.2h1M40.2 132h.4M40.8 131.4h-.6v1.3M44.3 127.7h4.9M45.2 128.3l-.5-.1-.3 .3M45.7 128.2v1.3M46.4 128.2v1.3M47.7 128.5l-.2-.2-.5-.1v1.3M49 128.2v1.3l-.7-1.3v1.3M71.1 135.2h.4"/>
<path d="M71.7 134.6h-.6v1.2M88.4 139.6h.6M174.7 127h.6M168.6 147.4h.9M169 146.9v1M256.5 143h1M258 142.2h.8l-.5 1.3M84.6 179.7l-.4 1.2M88.8 179.7l-.4 1.2"/>
</g>
<g fill="#ffffc2" stroke="#ffffc2" stroke-width=".18">
<path d="M136.5 36.2h5.1v12.7h-5.1z"/>
<path d="M255.9 130.8h17.8v10.8h-17.8z"/>
<path d="M43.2 118.7h10.1v15.3h-10.1z"/>
<path d="M261.6 45.7h2.6v5.1h-2.6z"/>
<path d="M214.6 45.7h2.6v5.1h-2.6z"/>
<path d="M131.4 88.3h25.4v57.8h-25.4z"/>
<path d="M37.5 42.5h2.5v5.1h-2.5z"/>
</g>
<g fill="none" stroke="#840000" stroke-width=".25">
<path d="M136.5 36.2h5.1v12.7h-5.1zM207.3 36.2v3.8M207.8 35.8v1M207.8 37.6v1M207.8 39.4v1M254.3 36.2v3.8M254.8 35.8v1M254.8 37.6v1M254.8 39.4v1M37.5 42.5h2.5v5.1h-2.5zM214.6 45.7h2.6v5.1h-2.6zM261.6 45.7h2.6v5.1h-2.6z"/>
<path d="M229.9 98.6v.5h2.5v.5M229.9 96.5h2.5l-2.5 5.1h2.5zM43.2 118.7h10.1v15.3h-10.1zM54 108l2.5 1.2-2.5 1.3zM56.5 108v2.5h-.5M65 100.2h1M65.4 100.7h3.8M66.8 100.2h1M68.6 100.2h1M231.1 114.3l1.3 2.5h-2.5zM232.4 114.3h-2.5v.5M261 113h2.5l-1.2 2.6z"/>
<path d="M261 115.6h2.5M269.2 113h2.6l-1.3 2.6zM269.2 115.6h2.6M260 133.4v3.8M260.5 133v1M260.5 134.7v1.1M260.5 136.5v1M268.2 133.4v3.8M268.7 133v1M268.7 134.7v1.1M268.7 136.5v1"/>
<circle cx="208.7" cy="38.1" r="2.79"/>
<circle cx="255.7" cy="38.1" r="2.79"/>
<circle cx="67.3" cy="99.3" r="2.79"/>
<circle cx="261.4" cy="135.3" r="2.79"/>
<circle cx="269.6" cy="135.3" r="2.79"/>
</g>
<path d="M191.9 37.3h3.6v1.6h-3.6zM239.5 37.3h3.6v1.6h-3.6zM188.5 40.1h1.5v3.6h-1.5zM236.1 40.1h1.5v3.6h-1.5zM192.9 127.8h1.5v3.5h-1.5zM203.7 127.8h1.5v3.5h-1.5zM261.5 122h1.5v3.6h-1.5zM269.7 122h1.6v3.6h-1.6zM47.5 144.3h1.5v3.5h-1.5z" fill="none" stroke="#840000" stroke-width=".2"/>
<g fill="#840000" stroke="#840000" stroke-width=".18">
<path d="M260.7 135.3l1-.4v.7z"/>
<path d="M269 135.3l1-.4v.7z"/>
<path d="M255 38.1l1-.4v.8z"/>
<path d="M208 38.1l1-.4v.8z"/>
<path d="M65 185.2h.2v2.7h.9v.2h-1.1z"/>
<path d="M59.5 185.4h.1l-.5 .6v-.1z"/>
<path d="M70 185.9l.7-.4h.4v.2a1.32 1.32 0 0 0-1.2 1.7v.7h-.2v-.9a1.67 1.67 0 0 1 .3-1.3z"/>
<path d="M58.3 185.4a11.4 11.4 0 0 1 3.2 6.3h-1.9v-.2a7.3 7.3 0 0 0-1.4-5.9z"/>
<path d="M52.1 182.4h.1a9.5 9.5 0 0 1 5.1 2.1l-.1 .1a7.2 7.2 0 0 0-5.1-1.5z"/>
<path d="M62.1 185.9a1.28 1.28 0 0 1 1.8 0 1.28 1.28 0 0 1 .1 1.8 1.28 1.28 0 0 1-1.8 .1v-.3l.1 .2a1.07 1.07 0 0 0 1.7-.3 1.07 1.07 0 0 0-.7-1.6 1.07 1.07 0 0 0-1.4 .9v2.2h-.2v-1.7a1.46 1.46 0 0 1 .4-1.3z"/>
<path d="M67 186l.8-.4a1.24 1.24 0 0 1 1.3 1.2 1.24 1.24 0 0 1-1.2 1.3v-.2a1.02 1.02 0 0 0 .8-1.5 1.02 1.02 0 0 0-1.7-.1 1.02 1.02 0 0 0 .7 1.6v.2a1.24 1.24 0 0 1-1-.8 1.24 1.24 0 0 1 .3-1.3z"/>
<path d="M52.1 189.4l6.8-5.7 1.7-1.3a.56 .56 0 0 1 .9 0l-.5 1.3a.17 .17 0 0 1-.2 .2 .17 .17 0 0 1-.1-.3l.2-.6a.18 .18 0 0 0-.1-.2 .18 .18 0 0 0-.2 0l-2 1.5-6.5 6.2z"/>
<path d="M71.9 186a1.26 1.26 0 0 1 1.4-.3 1.26 1.26 0 0 1 .8 1.2h-2.2v-.1h1.9a1.06 1.06 0 0 0-1.5-.9 1.06 1.06 0 0 0-.3 1.7 1.06 1.06 0 0 0 1.7-.2l.3-.1a1.26 1.26 0 0 1-1.9 .6 1.26 1.26 0 0 1-.2-1.9z"/>
<path d="M66.9 98.9h.8l-.4 1z"/>
<circle cx="262.3" cy="137" r=".25"/>
<circle cx="262.3" cy="133.5" r=".25"/>
<circle cx="270.5" cy="137" r=".25"/>
<circle cx="270.5" cy="133.5" r=".25"/>
<circle cx="256.5" cy="39.9" r=".25"/>
<circle cx="256.5" cy="36.3" r=".25"/>
<circle cx="209.5" cy="39.9" r=".25"/>
<circle cx="209.5" cy="36.3" r=".25"/>
<circle cx="60.2" cy="184.6" r=".63"/>
<circle cx="65.5" cy="98.4" r=".25"/>
<circle cx="69.1" cy="98.4" r=".25"/>
</g>
<circle cx="29.2" cy="182.2" r="1.27" fill="none" stroke="#840000" stroke-width="1.3"/>
<path d="M130.4 103.7h.7" fill="none" stroke="#a90000" stroke-width=".18"/>
<g fill="none" stroke="#0000c2" stroke-width=".18">
<path d="M15.2 15.2h76.2v51.5h-76.2zM94.6 15.2h78.8v51.5h-78.8zM41.8 37.4l-.1 .5 .1 .4 .2 .1 .4-.2v-.8M46.9 35.9l.6-.1-.1-.2-.3-.1-.2 .2 .1 .6h.4M54.3 36.2v.2M54.3 35.6v.1M56.5 39.6h.5M71.9 39.6v1.3M72.1 39.6l-.2 .1M74.7 37a1.47 1.47 0 0 1 0 1.9M81.4 39a1.46 1.46 0 0 1 0 2M41.8 40h.9"/>
<path d="M56.7 40.3l.3 .2M71.9 40.4l.2 .1M15.2 69.9h162v-54.7h104.7v141.6h-107.9v38.8h-79.4v-33h-79.4zM94.6 73v86.4M180.3 69.9h98.5M220 61.5v.1M223.8 66.9l.3 .1M224.1 66.9v1.1l-.2 .2M224.1 67.7l-.3 .1M235 62.5l-.1 .4 .1 .7M238.9 62.8v.9M239.2 66.6l-.1 .4 .1 .7"/>
<path d="M239.3 62.8l-.4 .1M243.1 66.9v.9M243.5 66.9l-.4 .2M249.3 67.8h.8M249.3 66.9l.4-.4v1.3M254.6 66.9l.1 .8 .3 .1 .1-.1M255.1 66.9v.9M42.5 90.5v1.1l.2 .2M52.9 91.3l.5 .2v.2l-.4 .1M52.9 91h.5M54 91.7l-.1 .2M117.3 84.8l-.3-.1-.2 .2v.2l.5 .1v.3h-.5"/>
<path d="M107 138.4h.9M108.6 138.1l.9 .3-.9 .4M141.7 159.3v.7M142 159.3l-.3 .2M149.4 159.3l.1 .2v.5M150 159.9v.1M150 159.4v.1M203.2 147h.5M203.4 146.6v1l.3 .2M210.9 150.9l.1 .4-.1 .8M212.4 147h.3M212.4 147.4l.3 .1 .1 .1-.2 .2h-.3"/>
<path d="M213.3 147.7v.1M213.3 147v.2M215.1 154.8v1.3M215.1 155.3l-.3-.1-.3 .2 .1 .6h.5M216.6 144.5l.4 1.3M219.6 142.4l.5 1.3M220.2 151.1v.8M220.6 151.1l-.4 .2M220.8 140.8l.2 .3-.6 .1M220.9 141.6l-.1 .1M223.1 144.9v.9M223.3 144.9l-.2 .1"/>
<path d="M226.1 142.9v.8M226.3 142.9l-.2 .1M227.7 145.1h1M227.7 145.5h1M230.2 145.6l.5 .2M230.7 141h1M230.7 141.4h1M230.7 143h1M230.7 143.4h1M230.8 144.5h-.6v.6l.5-.1M232.8 151.1h.5M233.2 141.5l.5 .2"/>
<path d="M233.7 142.4l-.5 .2M233.9 140.4h-.6l-.1 .6 .5-.1M233.9 143l-.8 .7h.8M235.1 144.5l-.2 .1a.81 .81 0 0 0 .2 1.2h.2M235.8 140.8l-.3 .1M237.9 142.6a.85 .85 0 0 0 .2 1.1h.2M238.1 153.2l-.1 .2 .1 .5M240 151.2l-.1 .1 .1 .6M242.6 153.2l-.3 .2v.4l.3 .2M15.2 165.7h31.8v29.9h-31.8zM49.5 165.7h41.9v29.9h-41.9zM101.8 160.1h.4"/>
<path d="M102 160.7l.2 .1M102.9 165.3h.4M103.1 165.9h.2M109 166.9h.4M109.1 166.6v.8l.3 .2M109.7 160.1v.7M110 160.1l-.3 .2M110.7 175.4h.7M110.9 165.3v.6M111.2 165.3l-.3 .2M111.5 165.8v.1M111.5 165.3v.1"/>
<path d="M113 174.8l-.4 .1M113.2 175.2l-.6 .6h.6M114.2 161.9l-.1 .1M114.3 161.5l-.2 .4 .1 .5M115.4 175.1l.1 .7 .3-.1M115.9 162.1h.5M116.1 161.4l-.3 1M118 175.3h.7M118 175.6h.7M118 178.1v1h.5M119.4 161.5l.4-.1 .2 .3-.7 .7h.7M120.2 174.8l-.2 .7h.6"/>
<path d="M120.3 178l-.9 1.4M120.4 175.1v.7M121.2 161.9h.7M121.2 162.2h.7M121.7 178a1.16 1.16 0 0 0 0 1.5M123.1 161.4h.6l-.3 .4M123.5 161.8l.2 .2v.2l-.2 .2M123.6 175.3h.4M124.1 174.8h-.5v1M140.8 177.6h.8M140.8 177.9h.8M142.8 178.1h.5"/>
<path d="M143.1 177.1v1M147 178l.1 .1 .3-.1M147.4 177.4v.7M148.2 175.4l.4 1.1M150.5 174.1l.6 .7M151.1 174.1l-.6 .7M151.3 162.6l-.2 .7M151.6 162.1a1.17 1.17 0 0 1 0 1.6M153.8 174.1v.7M153.9 174.1l-.1 .1M156.1 175.4l-.9 1.3M156.2 174.3h.7"/>
<path d="M156.2 174.6h.7M157.5 175.3a1.16 1.16 0 0 0 0 1.5M158.6 173.8h-.1a.54 .54 0 0 0-.4 .5 .54 .54 0 0 0 .4 .5h.1M161 175.6l.3 .1M161.3 175.4v.3M161.3 175.7l-.2 .2M161.3 175.7l.1 .2M161.5 175.6l-.2 .1M163.1 176.1a.34 .34 0 0 0 .5 .4M163.6 175.4a.34 .34 0 0 0-.5 .4M163.6 173.6a1.18 1.18 0 0 0 0 1.5M167.9 174.6l.2 .2h.3"/>
<path d="M168.4 174.2l-.3-.1-.2 .2M169.2 175.4v1.1M104.1 180.2h.8M104.1 180.5h.8M104.1 191.7h.8M104.1 192h.8M106.3 180.1l.3 .2v.4l-.3 .1M106.3 191.7l.3 .1v.4l-.3 .1M111.2 180.2l.3-.1 .2 .1M111.2 191.6v.7M111.2 191.7l.3-.1 .2 .1M111.7 180.2l.1-.1h.3v.7"/>
<path d="M111.7 180.2v.6M111.7 191.7v.6M111.7 191.7l.1-.1 .3 .1v.6M118 189.6v1h.5M120.3 189.6l-.9 1.3M121.7 189.5a1.17 1.17 0 0 0 0 1.5M140.8 189.1h.8M140.8 189.4h.8M142.8 189.6h.5M143.1 188.6v1M147 189.5l.1 .1 .3-.1M147.4 188.9v.7"/>
<path d="M148.2 187l.4 1M148.8 191.9l-.2 .1M149.1 192.3l-.5 .6h.6M150.5 185.7l.6 .6M151.1 185.7l-.6 .6M151.9 192.2v.6l.2 .1M153.8 185.7v.6M153.9 185.7l-.1 .1M156.1 186.9l-.9 1.3M156.2 185.8h.7M156.2 186.1h.7M157.5 186.8a1.17 1.17 0 0 0 0 1.6"/>
<path d="M158.6 185.4l-.1-.1a.54 .54 0 0 0-.4 .5 .54 .54 0 0 0 .4 .5h.1M161 187.1l.3 .1M161.3 187v.2M161.3 187.2l-.2 .2M161.3 187.2l.1 .2M161.5 187.1l-.2 .1M163.1 187.6a.34 .34 0 0 0 .5 .4M163.6 187a.34 .34 0 0 0-.5 .3M163.6 185.2a1.18 1.18 0 0 0 0 1.5M167.9 186.1l.2 .2h.3M168.4 185.7h-.3l-.2 .1M169.2 187v1"/>
</g>
<g fill="none" stroke="#0000c2" stroke-width=".51">
<path d="M25.2 18.3a.61 .61 0 0 1 .6-.2 .61 .61 0 0 1 .5 .5 1.49 1.49 0 0 1-.5 2 .65 .65 0 0 1-.7-.4 2.17 2.17 0 0 1 .1-1.9zM33.6 18.1l-.2 .1 .2 .1M45.1 19v2.5M45.8 19l-.7 .1M58.1 19.1l.3-.1 .7 .1M132.9 19v2.5M133.6 19l-.7 .1M146 19.1l.2-.1 .7 .1M45.1 20.5l.7 .1M58.1 20.5l.3 .1 .7-.1M132.9 20.5l.7 .1M146 20.5l.2 .1 .7-.1"/>
<path d="M193.9 20.5l.3 .1M67.6 72.5a2.98 2.98 0 0 0 0 3.6M81 73.7l-.7-.1-.5 .4v.8l.2 .3 .3 .2 .7-.2M81 72.7v2.6M121.3 72.8l-1-.1v2.6l1-.2M145.5 72.7v2.2l.3 .4M149.6 73.7l-.6-.1-.4 .3 .1 .4 .9 .2 .1 .3-.1 .3-.3 .2-.7-.2M169.1 73.6h-.3l-.3 .2M170.6 73.6h-.5l-.3 .3v1l.1 .2 .7 .2M171 74.2l-1.2 .2M86.2 169.4a.69 .69 0 0 1 .9 .5v.8a.69 .69 0 0 1-.9 .4"/>
</g>
<g fill="none" stroke="#009600" stroke-width=".18">
<path d="M27.3 37.5v6.3h6.4M102.9 35.6v9.5h29.8M109.2 33v7h23.5M130.2 37.5h2.5M145.4 37.5h2.6M158.7 33.7v6.3h-13.3M165.7 36.2v8.9h-20.3M186.7 38.1h4.4M189.2 38.1v1.3M196.2 38.1h5.7M209.5 29.2v3.8M234.3 38.1h4.5"/>
<path d="M236.9 38.1v1.3M243.8 38.1h5.1M256.5 29.2v3.8M33.7 46.4h-6.4v5.7M128.9 47.6h3.8M132.7 42.5h-3.8v12.1M145.4 47.6h2.6M145.4 42.5h2.6v9.6h-19.1M189.2 44.5v9.5M209.5 43.2v3.8h1.3M210.8 49.5h-1.3v4.5M236.9 44.5v9.5"/>
<path d="M256.5 43.2v3.8h1.3M257.8 49.5h-1.3v4.5M24.1 94v34.3M24.1 98.4h38.1M62.2 87h-3.8v11.4M72.4 87h3.8v11.4M72.4 98.4h8.9M81.3 94v42.5M103.5 96.5v1.3h25.4M108.6 97.8v.6M120 85.1v6.3h8.9M120 97.8v.6"/>
<path d="M127 91.4v3.2h1.9M159.4 97.8h19.7M159.4 91.4h2.5M159.4 94.6h56.5M175.9 97.8v3.2h-6.4M175.9 80.6v-1.9h-14v15.9M175.9 85.7v1.9M187.3 94.6v3.2h-3.2M191.1 94.6v1.9M202.6 94.6v1.9M231.1 94.6v.7M270.5 94.6v15.9"/>
<path d="M273.7 88.9v5.7h-52.7M24.1 109.2h27.3M48.3 109.2v7M59.1 109.2h8.2M67.3 106v8.9h-16.5v1.3M103.5 109.9v1.2h25.4M108.6 104.1h20.3M108.6 103.5v2.5M108.6 111.1v.7M108.6 116.8v2.6M108.6 117.5h20.3M120 103.5v.6"/>
<path d="M120 111.1v.7M120 116.8v.7M159.4 111.1h19.7M159.4 101h5.1M159.4 114.3h5.1M159.4 108h56.5M175.9 111.1v3.2h-6.4M187.3 108v3.1h-3.2M191.1 101.6v1.3h11.5M191.1 108v1.9M191.1 114.9v.7M202.6 101.6v1.9"/>
<path d="M204.5 117.5v9.5M231.1 102.9v.6M231.1 108v3.8M231.1 119.4v3.2M262.3 108v2.5M262.3 118.1v3.2M270.5 118.1v3.2M273.7 103.5v4.5h-52.7M24.1 133.4v1.2M24.1 139.7v1.9h24.2M24.1 126.4h16.5M38.7 126.4v2.5h1.9"/>
<path d="M48.3 136.5v7M50.8 136.5v1.3h-2.5M55.9 126.4h25.4M128.9 123.8h-8.9v4.5M159.4 123.8h1.9M159.4 139.1h94M159.4 135.3h94M159.4 120.7h45.1M161.3 120.7v6.3h-1.9M167 120.7v3.1M167 128.9v1.3M193.7 120.7v6.3"/>
<path d="M193.7 132.1v7M204.5 132.1v3.2M48.3 148.6v2.5M81.3 141.6v9.5M138.4 148.6v5.7M142.2 148.6v1.3M146 148.6v1.3M149.9 148.6v1.3h-11.5M262.3 144.1v2h8.2M270.5 144.1v4.5M76.8 185.4v4.5M81.9 185.4v4.5"/>
<path d="M87 185.4v4.5"/>
</g>
<g fill="#009600" stroke="#009600" stroke-width=".18">
<circle cx="38.7" cy="126.4" r=".46"/>
<circle cx="24.1" cy="109.2" r=".46"/>
<circle cx="24.1" cy="126.4" r=".46"/>
<circle cx="24.1" cy="98.4" r=".46"/>
<circle cx="24.1" cy="141.6" r=".46"/>
<circle cx="48.3" cy="141.6" r=".46"/>
<circle cx="58.4" cy="98.4" r=".46"/>
<circle cx="76.2" cy="98.4" r=".46"/>
<circle cx="81.3" cy="98.4" r=".46"/>
<circle cx="81.3" cy="126.4" r=".46"/>
<circle cx="48.3" cy="137.8" r=".46"/>
<circle cx="128.9" cy="47.6" r=".46"/>
<circle cx="128.9" cy="52.1" r=".46"/>
<circle cx="148" cy="47.6" r=".46"/>
<circle cx="48.3" cy="109.2" r=".46"/>
<circle cx="67.3" cy="109.2" r=".46"/>
<circle cx="108.6" cy="97.8" r=".46"/>
<circle cx="120" cy="104.1" r=".46"/>
<circle cx="127" cy="91.4" r=".46"/>
<circle cx="108.6" cy="111.1" r=".46"/>
<circle cx="161.3" cy="123.8" r=".46"/>
<circle cx="142.2" cy="149.9" r=".46"/>
<circle cx="146" cy="149.9" r=".46"/>
<circle cx="202.6" cy="94.6" r=".46"/>
<circle cx="202.6" cy="102.9" r=".46"/>
<circle cx="161.9" cy="91.4" r=".46"/>
<circle cx="175.9" cy="97.8" r=".46"/>
<circle cx="189.2" cy="38.1" r=".46"/>
<circle cx="187.3" cy="108" r=".46"/>
<circle cx="191.1" cy="108" r=".46"/>
<circle cx="167" cy="120.7" r=".46"/>
<circle cx="161.3" cy="120.7" r=".46"/>
<circle cx="175.9" cy="111.1" r=".46"/>
<circle cx="120" cy="117.5" r=".46"/>
<circle cx="120" cy="111.1" r=".46"/>
<circle cx="120" cy="97.8" r=".46"/>
<circle cx="138.4" cy="149.9" r=".46"/>
<circle cx="108.6" cy="104.1" r=".46"/>
<circle cx="108.6" cy="117.5" r=".46"/>
<circle cx="191.1" cy="94.6" r=".46"/>
<circle cx="187.3" cy="94.6" r=".46"/>
<circle cx="161.9" cy="94.6" r=".46"/>
<circle cx="193.7" cy="139.1" r=".46"/>
<circle cx="204.5" cy="135.3" r=".46"/>
<circle cx="193.7" cy="120.7" r=".46"/>
<circle cx="204.5" cy="120.7" r=".46"/>
<circle cx="231.1" cy="94.6" r=".46"/>
<circle cx="231.1" cy="108" r=".46"/>
<circle cx="236.9" cy="38.1" r=".46"/>
<circle cx="262.3" cy="108" r=".46"/>
<circle cx="270.5" cy="94.6" r=".46"/>
<circle cx="270.5" cy="146.1" r=".46"/>
</g>
<use href="#words"/>
</svg>
